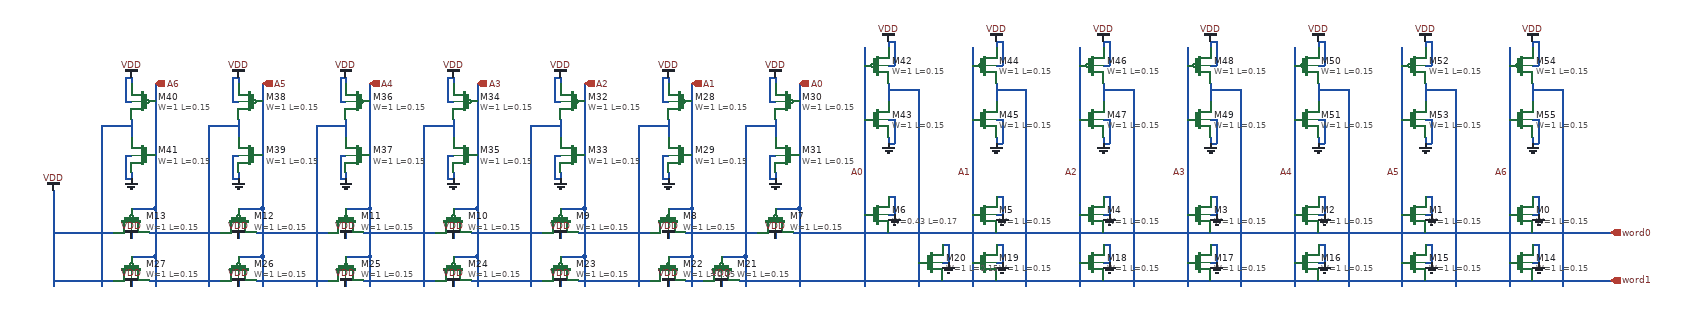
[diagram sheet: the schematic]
v {xschem version=3.4.6 file_version=1.2}
G {}
K {}
V {}
S {}
E {}
N 1450 -60 1450 0 { lab=#net1}
N 1360 -60 1360 0 { lab=A0}
N 1630 -60 1630 0 { lab=#net2}
N 1540 -60 1540 0 { lab=A1}
N 1810 -60 1810 0 { lab=#net3}
N 1720 -60 1720 0 { lab=A2}
N 1990 -60 1990 0 { lab=#net4}
N 1900 -60 1900 0 { lab=A3}
N 2170 -60 2170 0 { lab=#net5}
N 2080 -60 2080 0 { lab=A4}
N 2350 -60 2350 0 { lab=#net6}
N 2260 -60 2260 0 { lab=A5}
N 2530 -60 2530 0 { lab=#net7}
N 2440 -60 2440 0 { lab=A6}
N 1070 -60 1070 0 {lab=A1}
N 980 -30 980 0 {lab=#net8}
N 2530 0 2530 80 {lab=#net7}
N 2520 70 2610 70 {lab=word0}
N 2480 40 2490 40 {lab=GND}
N 2490 10 2490 40 {lab=GND}
N 2480 10 2490 10 {lab=GND}
N 2440 0 2440 40 {lab=A6}
N 2440 40 2440 80 {lab=A6}
N 2430 70 2480 70 {lab=word0}
N 2480 70 2520 70 {lab=word0}
N 2350 0 2350 80 {lab=#net6}
N 2340 70 2430 70 {lab=word0}
N 2300 40 2310 40 {lab=GND}
N 2310 10 2310 40 {lab=GND}
N 2300 10 2310 10 {lab=GND}
N 2260 0 2260 40 {lab=A5}
N 2260 40 2260 80 {lab=A5}
N 2250 70 2300 70 {lab=word0}
N 2300 70 2340 70 {lab=word0}
N 2170 0 2170 80 {lab=#net5}
N 2160 70 2250 70 {lab=word0}
N 2120 40 2130 40 {lab=GND}
N 2130 10 2130 40 {lab=GND}
N 2120 10 2130 10 {lab=GND}
N 2080 0 2080 40 {lab=A4}
N 2080 40 2080 80 {lab=A4}
N 2070 70 2120 70 {lab=word0}
N 2120 70 2160 70 {lab=word0}
N 1990 0 1990 80 {lab=#net4}
N 1980 70 2070 70 {lab=word0}
N 1940 40 1950 40 {lab=GND}
N 1950 10 1950 40 {lab=GND}
N 1940 10 1950 10 {lab=GND}
N 1900 0 1900 40 {lab=A3}
N 1900 40 1900 80 {lab=A3}
N 1890 70 1940 70 {lab=word0}
N 1940 70 1980 70 {lab=word0}
N 1810 0 1810 80 {lab=#net3}
N 1800 70 1890 70 {lab=word0}
N 1760 40 1770 40 {lab=GND}
N 1770 10 1770 40 {lab=GND}
N 1760 10 1770 10 {lab=GND}
N 1720 0 1720 40 {lab=A2}
N 1720 40 1720 80 {lab=A2}
N 1710 70 1760 70 {lab=word0}
N 1760 70 1800 70 {lab=word0}
N 1630 0 1630 80 {lab=#net2}
N 1620 70 1710 70 {lab=word0}
N 1580 40 1590 40 {lab=GND}
N 1590 10 1590 40 {lab=GND}
N 1580 10 1590 10 {lab=GND}
N 1540 0 1540 40 {lab=A1}
N 1540 40 1540 80 {lab=A1}
N 1530 70 1580 70 {lab=word0}
N 1580 70 1620 70 {lab=word0}
N 1450 0 1450 80 {lab=#net1}
N 1440 70 1530 70 {lab=word0}
N 1400 40 1410 40 {lab=GND}
N 1410 10 1410 40 {lab=GND}
N 1400 10 1410 10 {lab=GND}
N 1360 0 1360 40 {lab=A0}
N 1360 40 1360 80 {lab=A0}
N 1350 70 1400 70 {lab=word0}
N 1400 70 1440 70 {lab=word0}
N 1260 70 1350 70 { lab=word0}
N 1210 30 1250 30 {lab=A0}
N 1210 70 1210 80 {lab=VDD}
N 1240 70 1260 70 {lab=word0}
N 1170 70 1180 70 {lab=#net9}
N 1250 0 1250 30 {lab=A0}
N 1250 30 1250 80 {lab=A0}
N 1160 0 1160 80 {lab=#net10}
N 1080 70 1170 70 {lab=#net9}
N 1030 30 1070 30 {lab=A1}
N 1030 70 1030 80 {lab=VDD}
N 1060 70 1080 70 {lab=#net9}
N 990 70 1000 70 {lab=#net11}
N 1070 0 1070 30 {lab=A1}
N 1070 30 1070 80 {lab=A1}
N 980 0 980 80 {lab=#net8}
N 900 70 990 70 {lab=#net11}
N 850 30 890 30 {lab=A2}
N 850 70 850 80 {lab=VDD}
N 880 70 900 70 {lab=#net11}
N 810 70 820 70 {lab=#net12}
N 890 0 890 30 {lab=A2}
N 890 30 890 80 {lab=A2}
N 800 0 800 80 {lab=#net13}
N 720 70 810 70 {lab=#net12}
N 670 30 710 30 {lab=A3}
N 670 70 670 80 {lab=VDD}
N 700 70 720 70 {lab=#net12}
N 630 70 640 70 {lab=#net14}
N 710 0 710 30 {lab=A3}
N 710 30 710 80 {lab=A3}
N 620 0 620 80 {lab=#net15}
N 540 70 630 70 {lab=#net14}
N 490 30 530 30 {lab=A4}
N 490 70 490 80 {lab=VDD}
N 520 70 540 70 {lab=#net14}
N 450 70 460 70 {lab=#net16}
N 530 0 530 30 {lab=A4}
N 530 30 530 80 {lab=A4}
N 440 0 440 80 {lab=#net17}
N 360 70 450 70 {lab=#net16}
N 310 30 350 30 {lab=A5}
N 310 70 310 80 {lab=VDD}
N 340 70 360 70 {lab=#net16}
N 270 70 280 70 {lab=#net18}
N 350 0 350 30 {lab=A5}
N 350 30 350 80 {lab=A5}
N 260 0 260 80 {lab=#net19}
N 180 70 270 70 {lab=#net18}
N 130 30 170 30 {lab=A6}
N 130 70 130 80 {lab=VDD}
N 160 70 180 70 {lab=#net18}
N 90 70 100 70 {lab=VDD}
N 170 0 170 30 {lab=A6}
N 170 30 170 80 {lab=A6}
N 80 0 80 80 {lab=#net20}
N 0 70 90 70 {lab=VDD}
N 0 0 0 80 { lab=VDD}
N 2530 80 2530 160 {lab=#net7}
N 2520 150 2610 150 {lab=word1}
N 2480 120 2490 120 {lab=GND}
N 2490 90 2490 120 {lab=GND}
N 2480 90 2490 90 {lab=GND}
N 2440 80 2440 120 {lab=A6}
N 2440 120 2440 160 {lab=A6}
N 2430 150 2480 150 {lab=word1}
N 2480 150 2520 150 {lab=word1}
N 2350 80 2350 160 {lab=#net6}
N 2340 150 2430 150 {lab=word1}
N 2300 120 2310 120 {lab=GND}
N 2310 90 2310 120 {lab=GND}
N 2300 90 2310 90 {lab=GND}
N 2260 80 2260 120 {lab=A5}
N 2260 120 2260 160 {lab=A5}
N 2250 150 2300 150 {lab=word1}
N 2300 150 2340 150 {lab=word1}
N 2170 80 2170 160 {lab=#net5}
N 2160 150 2250 150 {lab=word1}
N 2120 120 2130 120 {lab=GND}
N 2130 90 2130 120 {lab=GND}
N 2120 90 2130 90 {lab=GND}
N 2080 80 2080 120 {lab=A4}
N 2080 120 2080 160 {lab=A4}
N 2070 150 2120 150 {lab=word1}
N 2120 150 2160 150 {lab=word1}
N 1990 80 1990 160 {lab=#net4}
N 1980 150 2070 150 {lab=word1}
N 1940 120 1950 120 {lab=GND}
N 1950 90 1950 120 {lab=GND}
N 1940 90 1950 90 {lab=GND}
N 1900 80 1900 120 {lab=A3}
N 1900 120 1900 160 {lab=A3}
N 1890 150 1940 150 {lab=word1}
N 1940 150 1980 150 {lab=word1}
N 1810 80 1810 160 {lab=#net3}
N 1800 150 1890 150 {lab=word1}
N 1760 120 1770 120 {lab=GND}
N 1770 90 1770 120 {lab=GND}
N 1760 90 1770 90 {lab=GND}
N 1720 80 1720 120 {lab=A2}
N 1720 120 1720 160 {lab=A2}
N 1710 150 1760 150 {lab=word1}
N 1760 150 1800 150 {lab=word1}
N 1630 80 1630 160 {lab=#net2}
N 1620 150 1710 150 {lab=word1}
N 1580 120 1590 120 {lab=GND}
N 1590 90 1590 120 {lab=GND}
N 1580 90 1590 90 {lab=GND}
N 1540 80 1540 120 {lab=A1}
N 1540 120 1540 160 {lab=A1}
N 1530 150 1580 150 {lab=word1}
N 1580 150 1620 150 {lab=word1}
N 1490 120 1500 120 {lab=GND}
N 1500 90 1500 120 {lab=GND}
N 1490 90 1500 90 {lab=GND}
N 1450 80 1450 120 {lab=#net1}
N 1450 120 1450 160 {lab=#net1}
N 1440 150 1490 150 {lab=word1}
N 1490 150 1530 150 {lab=word1}
N 1360 80 1360 160 {lab=A0}
N 1350 150 1440 150 {lab=word1}
N 1260 150 1350 150 { lab=word1}
N 1250 80 1250 160 {lab=A0}
N 1170 150 1260 150 {lab=word1}
N 1120 110 1160 110 {lab=#net10}
N 1120 150 1120 160 {lab=VDD}
N 1150 150 1170 150 {lab=word1}
N 1080 150 1090 150 {lab=#net21}
N 1160 80 1160 110 {lab=#net10}
N 1160 110 1160 160 {lab=#net10}
N 1030 110 1070 110 {lab=A1}
N 1030 150 1030 160 {lab=VDD}
N 1060 150 1080 150 {lab=#net21}
N 990 150 1000 150 {lab=#net22}
N 1070 80 1070 110 {lab=A1}
N 1070 110 1070 160 {lab=A1}
N 980 80 980 160 {lab=#net8}
N 900 150 990 150 {lab=#net22}
N 850 110 890 110 {lab=A2}
N 850 150 850 160 {lab=VDD}
N 880 150 900 150 {lab=#net22}
N 810 150 820 150 {lab=#net23}
N 890 80 890 110 {lab=A2}
N 890 110 890 160 {lab=A2}
N 800 80 800 160 {lab=#net13}
N 720 150 810 150 {lab=#net23}
N 670 110 710 110 {lab=A3}
N 670 150 670 160 {lab=VDD}
N 700 150 720 150 {lab=#net23}
N 630 150 640 150 {lab=#net24}
N 710 80 710 110 {lab=A3}
N 710 110 710 160 {lab=A3}
N 620 80 620 160 {lab=#net15}
N 540 150 630 150 {lab=#net24}
N 490 110 530 110 {lab=A4}
N 490 150 490 160 {lab=VDD}
N 520 150 540 150 {lab=#net24}
N 450 150 460 150 {lab=#net25}
N 530 80 530 110 {lab=A4}
N 530 110 530 160 {lab=A4}
N 440 80 440 160 {lab=#net17}
N 360 150 450 150 {lab=#net25}
N 310 110 350 110 {lab=A5}
N 310 150 310 160 {lab=VDD}
N 340 150 360 150 {lab=#net25}
N 270 150 280 150 {lab=#net26}
N 350 80 350 110 {lab=A5}
N 350 110 350 160 {lab=A5}
N 260 80 260 160 {lab=#net19}
N 180 150 270 150 {lab=#net26}
N 130 110 170 110 {lab=A6}
N 130 150 130 160 {lab=VDD}
N 160 150 180 150 {lab=#net26}
N 90 150 100 150 {lab=VDD}
N 170 80 170 110 {lab=A6}
N 170 110 170 160 {lab=A6}
N 80 80 80 160 {lab=#net20}
N 0 150 90 150 {lab=VDD}
N 0 80 0 160 { lab=VDD}
N 1070 -180 1070 -60 {lab=A1}
N 1020 -150 1030 -150 {lab=VDD}
N 1020 -190 1020 -150 {lab=VDD}
N 1020 -190 1030 -190 {lab=VDD}
N 1030 -190 1030 -180 {lab=VDD}
N 1030 -120 1030 -90 {lab=#net8}
N 1020 -60 1030 -60 {lab=GND}
N 1020 -60 1020 -20 {lab=GND}
N 1020 -20 1030 -20 {lab=GND}
N 1030 -30 1030 -20 {lab=GND}
N 980 -110 1030 -110 {lab=#net8}
N 980 -110 980 -30 {lab=#net8}
N 1250 -60 1250 0 {lab=A0}
N 1160 -30 1160 0 {lab=#net10}
N 1250 -180 1250 -60 {lab=A0}
N 1200 -150 1210 -150 {lab=VDD}
N 1200 -190 1200 -150 {lab=VDD}
N 1200 -190 1210 -190 {lab=VDD}
N 1210 -190 1210 -180 {lab=VDD}
N 1210 -120 1210 -90 {lab=#net10}
N 1200 -60 1210 -60 {lab=GND}
N 1200 -60 1200 -20 {lab=GND}
N 1200 -20 1210 -20 {lab=GND}
N 1210 -30 1210 -20 {lab=GND}
N 1160 -110 1210 -110 {lab=#net10}
N 1160 -110 1160 -30 {lab=#net10}
N 890 -60 890 0 {lab=A2}
N 800 -30 800 0 {lab=#net13}
N 890 -180 890 -60 {lab=A2}
N 840 -150 850 -150 {lab=VDD}
N 840 -190 840 -150 {lab=VDD}
N 840 -190 850 -190 {lab=VDD}
N 850 -190 850 -180 {lab=VDD}
N 850 -120 850 -90 {lab=#net13}
N 840 -60 850 -60 {lab=GND}
N 840 -60 840 -20 {lab=GND}
N 840 -20 850 -20 {lab=GND}
N 850 -30 850 -20 {lab=GND}
N 800 -110 850 -110 {lab=#net13}
N 800 -110 800 -30 {lab=#net13}
N 710 -60 710 0 {lab=A3}
N 620 -30 620 0 {lab=#net15}
N 710 -180 710 -60 {lab=A3}
N 660 -150 670 -150 {lab=VDD}
N 660 -190 660 -150 {lab=VDD}
N 660 -190 670 -190 {lab=VDD}
N 670 -190 670 -180 {lab=VDD}
N 670 -120 670 -90 {lab=#net15}
N 660 -60 670 -60 {lab=GND}
N 660 -60 660 -20 {lab=GND}
N 660 -20 670 -20 {lab=GND}
N 670 -30 670 -20 {lab=GND}
N 620 -110 670 -110 {lab=#net15}
N 620 -110 620 -30 {lab=#net15}
N 530 -60 530 0 {lab=A4}
N 440 -30 440 0 {lab=#net17}
N 530 -180 530 -60 {lab=A4}
N 480 -150 490 -150 {lab=VDD}
N 480 -190 480 -150 {lab=VDD}
N 480 -190 490 -190 {lab=VDD}
N 490 -190 490 -180 {lab=VDD}
N 490 -120 490 -90 {lab=#net17}
N 480 -60 490 -60 {lab=GND}
N 480 -60 480 -20 {lab=GND}
N 480 -20 490 -20 {lab=GND}
N 490 -30 490 -20 {lab=GND}
N 440 -110 490 -110 {lab=#net17}
N 440 -110 440 -30 {lab=#net17}
N 350 -60 350 0 {lab=A5}
N 260 -30 260 0 {lab=#net19}
N 350 -180 350 -60 {lab=A5}
N 300 -150 310 -150 {lab=VDD}
N 300 -190 300 -150 {lab=VDD}
N 300 -190 310 -190 {lab=VDD}
N 310 -190 310 -180 {lab=VDD}
N 310 -120 310 -90 {lab=#net19}
N 300 -60 310 -60 {lab=GND}
N 300 -60 300 -20 {lab=GND}
N 300 -20 310 -20 {lab=GND}
N 310 -30 310 -20 {lab=GND}
N 260 -110 310 -110 {lab=#net19}
N 260 -110 260 -30 {lab=#net19}
N 170 -60 170 0 {lab=A6}
N 80 -30 80 0 {lab=#net20}
N 170 -180 170 -60 {lab=A6}
N 120 -150 130 -150 {lab=VDD}
N 120 -190 120 -150 {lab=VDD}
N 120 -190 130 -190 {lab=VDD}
N 130 -190 130 -180 {lab=VDD}
N 130 -120 130 -90 {lab=#net20}
N 120 -60 130 -60 {lab=GND}
N 120 -60 120 -20 {lab=GND}
N 120 -20 130 -20 {lab=GND}
N 130 -30 130 -20 {lab=GND}
N 80 -110 130 -110 {lab=#net20}
N 80 -110 80 -30 {lab=#net20}
N 1360 -120 1360 -60 {lab=A0}
N 1450 -90 1450 -60 {lab=#net1}
N 1360 -240 1360 -120 {lab=A0}
N 1400 -210 1410 -210 {lab=VDD}
N 1410 -250 1410 -210 {lab=VDD}
N 1400 -250 1410 -250 {lab=VDD}
N 1400 -250 1400 -240 {lab=VDD}
N 1400 -180 1400 -150 {lab=#net1}
N 1400 -120 1410 -120 {lab=GND}
N 1410 -120 1410 -80 {lab=GND}
N 1400 -80 1410 -80 {lab=GND}
N 1400 -90 1400 -80 {lab=GND}
N 1400 -170 1450 -170 {lab=#net1}
N 1450 -170 1450 -90 {lab=#net1}
N 1540 -120 1540 -60 {lab=A1}
N 1630 -90 1630 -60 {lab=#net2}
N 1540 -240 1540 -120 {lab=A1}
N 1580 -210 1590 -210 {lab=VDD}
N 1590 -250 1590 -210 {lab=VDD}
N 1580 -250 1590 -250 {lab=VDD}
N 1580 -250 1580 -240 {lab=VDD}
N 1580 -180 1580 -150 {lab=#net2}
N 1580 -120 1590 -120 {lab=GND}
N 1590 -120 1590 -80 {lab=GND}
N 1580 -80 1590 -80 {lab=GND}
N 1580 -90 1580 -80 {lab=GND}
N 1580 -170 1630 -170 {lab=#net2}
N 1630 -170 1630 -90 {lab=#net2}
N 1720 -120 1720 -60 {lab=A2}
N 1810 -90 1810 -60 {lab=#net3}
N 1720 -240 1720 -120 {lab=A2}
N 1760 -210 1770 -210 {lab=VDD}
N 1770 -250 1770 -210 {lab=VDD}
N 1760 -250 1770 -250 {lab=VDD}
N 1760 -250 1760 -240 {lab=VDD}
N 1760 -180 1760 -150 {lab=#net3}
N 1760 -120 1770 -120 {lab=GND}
N 1770 -120 1770 -80 {lab=GND}
N 1760 -80 1770 -80 {lab=GND}
N 1760 -90 1760 -80 {lab=GND}
N 1760 -170 1810 -170 {lab=#net3}
N 1810 -170 1810 -90 {lab=#net3}
N 1900 -120 1900 -60 {lab=A3}
N 1990 -90 1990 -60 {lab=#net4}
N 1900 -240 1900 -120 {lab=A3}
N 1940 -210 1950 -210 {lab=VDD}
N 1950 -250 1950 -210 {lab=VDD}
N 1940 -250 1950 -250 {lab=VDD}
N 1940 -250 1940 -240 {lab=VDD}
N 1940 -180 1940 -150 {lab=#net4}
N 1940 -120 1950 -120 {lab=GND}
N 1950 -120 1950 -80 {lab=GND}
N 1940 -80 1950 -80 {lab=GND}
N 1940 -90 1940 -80 {lab=GND}
N 1940 -170 1990 -170 {lab=#net4}
N 1990 -170 1990 -90 {lab=#net4}
N 2080 -120 2080 -60 {lab=A4}
N 2170 -90 2170 -60 {lab=#net5}
N 2080 -240 2080 -120 {lab=A4}
N 2120 -210 2130 -210 {lab=VDD}
N 2130 -250 2130 -210 {lab=VDD}
N 2120 -250 2130 -250 {lab=VDD}
N 2120 -250 2120 -240 {lab=VDD}
N 2120 -180 2120 -150 {lab=#net5}
N 2120 -120 2130 -120 {lab=GND}
N 2130 -120 2130 -80 {lab=GND}
N 2120 -80 2130 -80 {lab=GND}
N 2120 -90 2120 -80 {lab=GND}
N 2120 -170 2170 -170 {lab=#net5}
N 2170 -170 2170 -90 {lab=#net5}
N 2260 -120 2260 -60 {lab=A5}
N 2350 -90 2350 -60 {lab=#net6}
N 2260 -240 2260 -120 {lab=A5}
N 2300 -210 2310 -210 {lab=VDD}
N 2310 -250 2310 -210 {lab=VDD}
N 2300 -250 2310 -250 {lab=VDD}
N 2300 -250 2300 -240 {lab=VDD}
N 2300 -180 2300 -150 {lab=#net6}
N 2300 -120 2310 -120 {lab=GND}
N 2310 -120 2310 -80 {lab=GND}
N 2300 -80 2310 -80 {lab=GND}
N 2300 -90 2300 -80 {lab=GND}
N 2300 -170 2350 -170 {lab=#net6}
N 2350 -170 2350 -90 {lab=#net6}
N 2440 -120 2440 -60 {lab=A6}
N 2530 -90 2530 -60 {lab=#net7}
N 2440 -240 2440 -120 {lab=A6}
N 2480 -210 2490 -210 {lab=VDD}
N 2490 -250 2490 -210 {lab=VDD}
N 2480 -250 2490 -250 {lab=VDD}
N 2480 -250 2480 -240 {lab=VDD}
N 2480 -180 2480 -150 {lab=#net7}
N 2480 -120 2490 -120 {lab=GND}
N 2490 -120 2490 -80 {lab=GND}
N 2480 -80 2490 -80 {lab=GND}
N 2480 -90 2480 -80 {lab=GND}
N 2480 -170 2530 -170 {lab=#net7}
N 2530 -170 2530 -90 {lab=#net7}
C {devices/vdd.sym} 0 0 0 0 {lab=VDD}
C {devices/lab_wire.sym} 1360 -30 0 0 {name=p1 lab=A0}
C {devices/lab_wire.sym} 1540 -30 0 0 {name=p3 lab=A1}
C {devices/lab_wire.sym} 1720 -30 0 0 {name=p5 lab=A2}
C {devices/lab_wire.sym} 1900 -30 0 0 {name=p7 lab=A3}
C {devices/lab_wire.sym} 2080 -30 0 0 {name=p9 lab=A4}
C {devices/lab_wire.sym} 2260 -30 0 0 {name=p11 lab=A5}
C {devices/lab_wire.sym} 2440 -30 0 0 {name=p13 lab=A6}
C {devices/ipin.sym} 1250 -180 3 1 {name=p14 lab=A0}
C {devices/ipin.sym} 1070 -180 3 1 {name=p16 lab=A1}
C {devices/ipin.sym} 890 -180 3 1 {name=p18 lab=A2}
C {devices/ipin.sym} 710 -180 3 1 {name=p20 lab=A3}
C {devices/ipin.sym} 530 -180 3 1 {name=p22 lab=A4}
C {devices/ipin.sym} 350 -180 3 1 {name=p24 lab=A5}
C {devices/ipin.sym} 170 -180 3 1 {name=p26 lab=A6}
C {devices/opin.sym} 2610 70 0 0 {name=p28 lab=word0}
C {sky130_fd_pr/nfet_01v8.sym} 2460 40 2 1 {name=M0
L=0.15
W=1
nf=1 
mult=1
ad="'int((nf+1)/2) * W/nf * 0.29'" 
pd="'2*int((nf+1)/2) * (W/nf + 0.29)'"
as="'int((nf+2)/2) * W/nf * 0.29'" 
ps="'2*int((nf+2)/2) * (W/nf + 0.29)'"
nrd="'0.29 / W'" nrs="'0.29 / W'"
sa=0 sb=0 sd=0
model=nfet_01v8
spiceprefix=X
}
C {devices/gnd.sym} 2490 40 3 0 {name=l0 lab=GND}
C {sky130_fd_pr/nfet_01v8.sym} 2280 40 2 1 {name=M1
L=0.15
W=1
nf=1 
mult=1
ad="'int((nf+1)/2) * W/nf * 0.29'" 
pd="'2*int((nf+1)/2) * (W/nf + 0.29)'"
as="'int((nf+2)/2) * W/nf * 0.29'" 
ps="'2*int((nf+2)/2) * (W/nf + 0.29)'"
nrd="'0.29 / W'" nrs="'0.29 / W'"
sa=0 sb=0 sd=0
model=nfet_01v8
spiceprefix=X
}
C {devices/gnd.sym} 2310 40 3 0 {name=l1 lab=GND}
C {sky130_fd_pr/nfet_01v8.sym} 2100 40 2 1 {name=M2
L=0.15
W=1
nf=1 
mult=1
ad="'int((nf+1)/2) * W/nf * 0.29'" 
pd="'2*int((nf+1)/2) * (W/nf + 0.29)'"
as="'int((nf+2)/2) * W/nf * 0.29'" 
ps="'2*int((nf+2)/2) * (W/nf + 0.29)'"
nrd="'0.29 / W'" nrs="'0.29 / W'"
sa=0 sb=0 sd=0
model=nfet_01v8
spiceprefix=X
}
C {devices/gnd.sym} 2130 40 3 0 {name=l2 lab=GND}
C {sky130_fd_pr/nfet_01v8.sym} 1920 40 2 1 {name=M3
L=0.15
W=1
nf=1 
mult=1
ad="'int((nf+1)/2) * W/nf * 0.29'" 
pd="'2*int((nf+1)/2) * (W/nf + 0.29)'"
as="'int((nf+2)/2) * W/nf * 0.29'" 
ps="'2*int((nf+2)/2) * (W/nf + 0.29)'"
nrd="'0.29 / W'" nrs="'0.29 / W'"
sa=0 sb=0 sd=0
model=nfet_01v8
spiceprefix=X
}
C {devices/gnd.sym} 1950 40 3 0 {name=l3 lab=GND}
C {sky130_fd_pr/nfet_01v8.sym} 1740 40 2 1 {name=M4
L=0.15
W=1
nf=1 
mult=1
ad="'int((nf+1)/2) * W/nf * 0.29'" 
pd="'2*int((nf+1)/2) * (W/nf + 0.29)'"
as="'int((nf+2)/2) * W/nf * 0.29'" 
ps="'2*int((nf+2)/2) * (W/nf + 0.29)'"
nrd="'0.29 / W'" nrs="'0.29 / W'"
sa=0 sb=0 sd=0
model=nfet_01v8
spiceprefix=X
}
C {devices/gnd.sym} 1770 40 3 0 {name=l4 lab=GND}
C {sky130_fd_pr/nfet_01v8.sym} 1560 40 2 1 {name=M5
L=0.15
W=1
nf=1 
mult=1
ad="'int((nf+1)/2) * W/nf * 0.29'" 
pd="'2*int((nf+1)/2) * (W/nf + 0.29)'"
as="'int((nf+2)/2) * W/nf * 0.29'" 
ps="'2*int((nf+2)/2) * (W/nf + 0.29)'"
nrd="'0.29 / W'" nrs="'0.29 / W'"
sa=0 sb=0 sd=0
model=nfet_01v8
spiceprefix=X
}
C {devices/gnd.sym} 1590 40 3 0 {name=l5 lab=GND}
C {sky130_fd_pr/nfet_01v8.sym} 1380 40 2 1 {name=M6
L=0.17
W=0.43
nf=1 
mult=1
ad="'int((nf+1)/2) * W/nf * 0.29'" 
pd="'2*int((nf+1)/2) * (W/nf + 0.29)'"
as="'int((nf+2)/2) * W/nf * 0.29'" 
ps="'2*int((nf+2)/2) * (W/nf + 0.29)'"
nrd="'0.29 / W'" nrs="'0.29 / W'"
sa=0 sb=0 sd=0
model=nfet_01v8
spiceprefix=X
}
C {devices/gnd.sym} 1410 40 3 0 {name=l6 lab=GND}
C {sky130_fd_pr/pfet_01v8.sym} 1210 50 3 1 {name=M7
L=0.15
W=1
nf=1
mult=1
ad="'int((nf+1)/2) * W/nf * 0.29'" 
pd="'2*int((nf+1)/2) * (W/nf + 0.29)'"
as="'int((nf+2)/2) * W/nf * 0.29'" 
ps="'2*int((nf+2)/2) * (W/nf + 0.29)'"
nrd="'0.29 / W'" nrs="'0.29 / W'"
sa=0 sb=0 sd=0
model=pfet_01v8
spiceprefix=X
}
C {devices/vdd.sym} 1210 80 3 0 {name=l7 lab=VDD}
C {sky130_fd_pr/pfet_01v8.sym} 1030 50 3 1 {name=M8
L=0.15
W=1
nf=1
mult=1
ad="'int((nf+1)/2) * W/nf * 0.29'" 
pd="'2*int((nf+1)/2) * (W/nf + 0.29)'"
as="'int((nf+2)/2) * W/nf * 0.29'" 
ps="'2*int((nf+2)/2) * (W/nf + 0.29)'"
nrd="'0.29 / W'" nrs="'0.29 / W'"
sa=0 sb=0 sd=0
model=pfet_01v8
spiceprefix=X
}
C {devices/vdd.sym} 1030 80 3 0 {name=l8 lab=VDD}
C {sky130_fd_pr/pfet_01v8.sym} 850 50 3 1 {name=M9
L=0.15
W=1
nf=1
mult=1
ad="'int((nf+1)/2) * W/nf * 0.29'" 
pd="'2*int((nf+1)/2) * (W/nf + 0.29)'"
as="'int((nf+2)/2) * W/nf * 0.29'" 
ps="'2*int((nf+2)/2) * (W/nf + 0.29)'"
nrd="'0.29 / W'" nrs="'0.29 / W'"
sa=0 sb=0 sd=0
model=pfet_01v8
spiceprefix=X
}
C {devices/vdd.sym} 850 80 3 0 {name=l9 lab=VDD}
C {sky130_fd_pr/pfet_01v8.sym} 670 50 3 1 {name=M10
L=0.15
W=1
nf=1
mult=1
ad="'int((nf+1)/2) * W/nf * 0.29'" 
pd="'2*int((nf+1)/2) * (W/nf + 0.29)'"
as="'int((nf+2)/2) * W/nf * 0.29'" 
ps="'2*int((nf+2)/2) * (W/nf + 0.29)'"
nrd="'0.29 / W'" nrs="'0.29 / W'"
sa=0 sb=0 sd=0
model=pfet_01v8
spiceprefix=X
}
C {devices/vdd.sym} 670 80 3 0 {name=l10 lab=VDD}
C {sky130_fd_pr/pfet_01v8.sym} 490 50 3 1 {name=M11
L=0.15
W=1
nf=1
mult=1
ad="'int((nf+1)/2) * W/nf * 0.29'" 
pd="'2*int((nf+1)/2) * (W/nf + 0.29)'"
as="'int((nf+2)/2) * W/nf * 0.29'" 
ps="'2*int((nf+2)/2) * (W/nf + 0.29)'"
nrd="'0.29 / W'" nrs="'0.29 / W'"
sa=0 sb=0 sd=0
model=pfet_01v8
spiceprefix=X
}
C {devices/vdd.sym} 490 80 3 0 {name=l11 lab=VDD}
C {sky130_fd_pr/pfet_01v8.sym} 310 50 3 1 {name=M12
L=0.15
W=1
nf=1
mult=1
ad="'int((nf+1)/2) * W/nf * 0.29'" 
pd="'2*int((nf+1)/2) * (W/nf + 0.29)'"
as="'int((nf+2)/2) * W/nf * 0.29'" 
ps="'2*int((nf+2)/2) * (W/nf + 0.29)'"
nrd="'0.29 / W'" nrs="'0.29 / W'"
sa=0 sb=0 sd=0
model=pfet_01v8
spiceprefix=X
}
C {devices/vdd.sym} 310 80 3 0 {name=l12 lab=VDD}
C {sky130_fd_pr/pfet_01v8.sym} 130 50 3 1 {name=M13
L=0.15
W=1
nf=1
mult=1
ad="'int((nf+1)/2) * W/nf * 0.29'" 
pd="'2*int((nf+1)/2) * (W/nf + 0.29)'"
as="'int((nf+2)/2) * W/nf * 0.29'" 
ps="'2*int((nf+2)/2) * (W/nf + 0.29)'"
nrd="'0.29 / W'" nrs="'0.29 / W'"
sa=0 sb=0 sd=0
model=pfet_01v8
spiceprefix=X
}
C {devices/vdd.sym} 130 80 3 0 {name=l13 lab=VDD}
C {devices/opin.sym} 2610 150 0 0 {name=p29 lab=word1}
C {sky130_fd_pr/nfet_01v8.sym} 2460 120 2 1 {name=M14
L=0.15
W=1
nf=1 
mult=1
ad="'int((nf+1)/2) * W/nf * 0.29'" 
pd="'2*int((nf+1)/2) * (W/nf + 0.29)'"
as="'int((nf+2)/2) * W/nf * 0.29'" 
ps="'2*int((nf+2)/2) * (W/nf + 0.29)'"
nrd="'0.29 / W'" nrs="'0.29 / W'"
sa=0 sb=0 sd=0
model=nfet_01v8
spiceprefix=X
}
C {devices/gnd.sym} 2490 120 3 0 {name=l14 lab=GND}
C {sky130_fd_pr/nfet_01v8.sym} 2280 120 2 1 {name=M15
L=0.15
W=1
nf=1 
mult=1
ad="'int((nf+1)/2) * W/nf * 0.29'" 
pd="'2*int((nf+1)/2) * (W/nf + 0.29)'"
as="'int((nf+2)/2) * W/nf * 0.29'" 
ps="'2*int((nf+2)/2) * (W/nf + 0.29)'"
nrd="'0.29 / W'" nrs="'0.29 / W'"
sa=0 sb=0 sd=0
model=nfet_01v8
spiceprefix=X
}
C {devices/gnd.sym} 2310 120 3 0 {name=l15 lab=GND}
C {sky130_fd_pr/nfet_01v8.sym} 2100 120 2 1 {name=M16
L=0.15
W=1
nf=1 
mult=1
ad="'int((nf+1)/2) * W/nf * 0.29'" 
pd="'2*int((nf+1)/2) * (W/nf + 0.29)'"
as="'int((nf+2)/2) * W/nf * 0.29'" 
ps="'2*int((nf+2)/2) * (W/nf + 0.29)'"
nrd="'0.29 / W'" nrs="'0.29 / W'"
sa=0 sb=0 sd=0
model=nfet_01v8
spiceprefix=X
}
C {devices/gnd.sym} 2130 120 3 0 {name=l16 lab=GND}
C {sky130_fd_pr/nfet_01v8.sym} 1920 120 2 1 {name=M17
L=0.15
W=1
nf=1 
mult=1
ad="'int((nf+1)/2) * W/nf * 0.29'" 
pd="'2*int((nf+1)/2) * (W/nf + 0.29)'"
as="'int((nf+2)/2) * W/nf * 0.29'" 
ps="'2*int((nf+2)/2) * (W/nf + 0.29)'"
nrd="'0.29 / W'" nrs="'0.29 / W'"
sa=0 sb=0 sd=0
model=nfet_01v8
spiceprefix=X
}
C {devices/gnd.sym} 1950 120 3 0 {name=l17 lab=GND}
C {sky130_fd_pr/nfet_01v8.sym} 1740 120 2 1 {name=M18
L=0.15
W=1
nf=1 
mult=1
ad="'int((nf+1)/2) * W/nf * 0.29'" 
pd="'2*int((nf+1)/2) * (W/nf + 0.29)'"
as="'int((nf+2)/2) * W/nf * 0.29'" 
ps="'2*int((nf+2)/2) * (W/nf + 0.29)'"
nrd="'0.29 / W'" nrs="'0.29 / W'"
sa=0 sb=0 sd=0
model=nfet_01v8
spiceprefix=X
}
C {devices/gnd.sym} 1770 120 3 0 {name=l18 lab=GND}
C {sky130_fd_pr/nfet_01v8.sym} 1560 120 2 1 {name=M19
L=0.15
W=1
nf=1 
mult=1
ad="'int((nf+1)/2) * W/nf * 0.29'" 
pd="'2*int((nf+1)/2) * (W/nf + 0.29)'"
as="'int((nf+2)/2) * W/nf * 0.29'" 
ps="'2*int((nf+2)/2) * (W/nf + 0.29)'"
nrd="'0.29 / W'" nrs="'0.29 / W'"
sa=0 sb=0 sd=0
model=nfet_01v8
spiceprefix=X
}
C {devices/gnd.sym} 1590 120 3 0 {name=l19 lab=GND}
C {sky130_fd_pr/nfet_01v8.sym} 1470 120 2 1 {name=M20
L=0.15
W=1
nf=1 
mult=1
ad="'int((nf+1)/2) * W/nf * 0.29'" 
pd="'2*int((nf+1)/2) * (W/nf + 0.29)'"
as="'int((nf+2)/2) * W/nf * 0.29'" 
ps="'2*int((nf+2)/2) * (W/nf + 0.29)'"
nrd="'0.29 / W'" nrs="'0.29 / W'"
sa=0 sb=0 sd=0
model=nfet_01v8
spiceprefix=X
}
C {devices/gnd.sym} 1500 120 3 0 {name=l20 lab=GND}
C {sky130_fd_pr/pfet_01v8.sym} 1120 130 3 1 {name=M21
L=0.15
W=1
nf=1
mult=1
ad="'int((nf+1)/2) * W/nf * 0.29'" 
pd="'2*int((nf+1)/2) * (W/nf + 0.29)'"
as="'int((nf+2)/2) * W/nf * 0.29'" 
ps="'2*int((nf+2)/2) * (W/nf + 0.29)'"
nrd="'0.29 / W'" nrs="'0.29 / W'"
sa=0 sb=0 sd=0
model=pfet_01v8
spiceprefix=X
}
C {devices/vdd.sym} 1120 160 3 0 {name=l21 lab=VDD}
C {sky130_fd_pr/pfet_01v8.sym} 1030 130 3 1 {name=M22
L=0.15
W=1
nf=1
mult=1
ad="'int((nf+1)/2) * W/nf * 0.29'" 
pd="'2*int((nf+1)/2) * (W/nf + 0.29)'"
as="'int((nf+2)/2) * W/nf * 0.29'" 
ps="'2*int((nf+2)/2) * (W/nf + 0.29)'"
nrd="'0.29 / W'" nrs="'0.29 / W'"
sa=0 sb=0 sd=0
model=pfet_01v8
spiceprefix=X
}
C {devices/vdd.sym} 1030 160 3 0 {name=l22 lab=VDD}
C {sky130_fd_pr/pfet_01v8.sym} 850 130 3 1 {name=M23
L=0.15
W=1
nf=1
mult=1
ad="'int((nf+1)/2) * W/nf * 0.29'" 
pd="'2*int((nf+1)/2) * (W/nf + 0.29)'"
as="'int((nf+2)/2) * W/nf * 0.29'" 
ps="'2*int((nf+2)/2) * (W/nf + 0.29)'"
nrd="'0.29 / W'" nrs="'0.29 / W'"
sa=0 sb=0 sd=0
model=pfet_01v8
spiceprefix=X
}
C {devices/vdd.sym} 850 160 3 0 {name=l23 lab=VDD}
C {sky130_fd_pr/pfet_01v8.sym} 670 130 3 1 {name=M24
L=0.15
W=1
nf=1
mult=1
ad="'int((nf+1)/2) * W/nf * 0.29'" 
pd="'2*int((nf+1)/2) * (W/nf + 0.29)'"
as="'int((nf+2)/2) * W/nf * 0.29'" 
ps="'2*int((nf+2)/2) * (W/nf + 0.29)'"
nrd="'0.29 / W'" nrs="'0.29 / W'"
sa=0 sb=0 sd=0
model=pfet_01v8
spiceprefix=X
}
C {devices/vdd.sym} 670 160 3 0 {name=l24 lab=VDD}
C {sky130_fd_pr/pfet_01v8.sym} 490 130 3 1 {name=M25
L=0.15
W=1
nf=1
mult=1
ad="'int((nf+1)/2) * W/nf * 0.29'" 
pd="'2*int((nf+1)/2) * (W/nf + 0.29)'"
as="'int((nf+2)/2) * W/nf * 0.29'" 
ps="'2*int((nf+2)/2) * (W/nf + 0.29)'"
nrd="'0.29 / W'" nrs="'0.29 / W'"
sa=0 sb=0 sd=0
model=pfet_01v8
spiceprefix=X
}
C {devices/vdd.sym} 490 160 3 0 {name=l25 lab=VDD}
C {sky130_fd_pr/pfet_01v8.sym} 310 130 3 1 {name=M26
L=0.15
W=1
nf=1
mult=1
ad="'int((nf+1)/2) * W/nf * 0.29'" 
pd="'2*int((nf+1)/2) * (W/nf + 0.29)'"
as="'int((nf+2)/2) * W/nf * 0.29'" 
ps="'2*int((nf+2)/2) * (W/nf + 0.29)'"
nrd="'0.29 / W'" nrs="'0.29 / W'"
sa=0 sb=0 sd=0
model=pfet_01v8
spiceprefix=X
}
C {devices/vdd.sym} 310 160 3 0 {name=l26 lab=VDD}
C {sky130_fd_pr/pfet_01v8.sym} 130 130 3 1 {name=M27
L=0.15
W=1
nf=1
mult=1
ad="'int((nf+1)/2) * W/nf * 0.29'" 
pd="'2*int((nf+1)/2) * (W/nf + 0.29)'"
as="'int((nf+2)/2) * W/nf * 0.29'" 
ps="'2*int((nf+2)/2) * (W/nf + 0.29)'"
nrd="'0.29 / W'" nrs="'0.29 / W'"
sa=0 sb=0 sd=0
model=pfet_01v8
spiceprefix=X
}
C {devices/vdd.sym} 130 160 3 0 {name=l27 lab=VDD}
C {sky130_fd_pr/pfet_01v8.sym} 1050 -150 2 0 {name=M28
L=0.15
W=1
nf=1
mult=1
ad="'int((nf+1)/2) * W/nf * 0.29'" 
pd="'2*int((nf+1)/2) * (W/nf + 0.29)'"
as="'int((nf+2)/2) * W/nf * 0.29'" 
ps="'2*int((nf+2)/2) * (W/nf + 0.29)'"
nrd="'0.29 / W'" nrs="'0.29 / W'"
sa=0 sb=0 sd=0
model=pfet_01v8
spiceprefix=X
}
C {sky130_fd_pr/nfet_01v8.sym} 1050 -60 2 0 {name=M29
L=0.15
W=1
nf=1 
mult=1
ad="'int((nf+1)/2) * W/nf * 0.29'" 
pd="'2*int((nf+1)/2) * (W/nf + 0.29)'"
as="'int((nf+2)/2) * W/nf * 0.29'" 
ps="'2*int((nf+2)/2) * (W/nf + 0.29)'"
nrd="'0.29 / W'" nrs="'0.29 / W'"
sa=0 sb=0 sd=0
model=nfet_01v8
spiceprefix=X
}
C {devices/vdd.sym} 1030 -190 0 0 {lab=VDD}
C {devices/gnd.sym} 1030 -20 0 0 {name=l28 lab=GND}
C {sky130_fd_pr/pfet_01v8.sym} 1230 -150 2 0 {name=M30
L=0.15
W=1
nf=1
mult=1
ad="'int((nf+1)/2) * W/nf * 0.29'" 
pd="'2*int((nf+1)/2) * (W/nf + 0.29)'"
as="'int((nf+2)/2) * W/nf * 0.29'" 
ps="'2*int((nf+2)/2) * (W/nf + 0.29)'"
nrd="'0.29 / W'" nrs="'0.29 / W'"
sa=0 sb=0 sd=0
model=pfet_01v8
spiceprefix=X
}
C {sky130_fd_pr/nfet_01v8.sym} 1230 -60 2 0 {name=M31
L=0.15
W=1
nf=1 
mult=1
ad="'int((nf+1)/2) * W/nf * 0.29'" 
pd="'2*int((nf+1)/2) * (W/nf + 0.29)'"
as="'int((nf+2)/2) * W/nf * 0.29'" 
ps="'2*int((nf+2)/2) * (W/nf + 0.29)'"
nrd="'0.29 / W'" nrs="'0.29 / W'"
sa=0 sb=0 sd=0
model=nfet_01v8
spiceprefix=X
}
C {devices/vdd.sym} 1210 -190 0 0 {lab=VDD}
C {devices/gnd.sym} 1210 -20 0 0 {name=l29 lab=GND}
C {sky130_fd_pr/pfet_01v8.sym} 870 -150 2 0 {name=M32
L=0.15
W=1
nf=1
mult=1
ad="'int((nf+1)/2) * W/nf * 0.29'" 
pd="'2*int((nf+1)/2) * (W/nf + 0.29)'"
as="'int((nf+2)/2) * W/nf * 0.29'" 
ps="'2*int((nf+2)/2) * (W/nf + 0.29)'"
nrd="'0.29 / W'" nrs="'0.29 / W'"
sa=0 sb=0 sd=0
model=pfet_01v8
spiceprefix=X
}
C {sky130_fd_pr/nfet_01v8.sym} 870 -60 2 0 {name=M33
L=0.15
W=1
nf=1 
mult=1
ad="'int((nf+1)/2) * W/nf * 0.29'" 
pd="'2*int((nf+1)/2) * (W/nf + 0.29)'"
as="'int((nf+2)/2) * W/nf * 0.29'" 
ps="'2*int((nf+2)/2) * (W/nf + 0.29)'"
nrd="'0.29 / W'" nrs="'0.29 / W'"
sa=0 sb=0 sd=0
model=nfet_01v8
spiceprefix=X
}
C {devices/vdd.sym} 850 -190 0 0 {lab=VDD}
C {devices/gnd.sym} 850 -20 0 0 {name=l30 lab=GND}
C {sky130_fd_pr/pfet_01v8.sym} 690 -150 2 0 {name=M34
L=0.15
W=1
nf=1
mult=1
ad="'int((nf+1)/2) * W/nf * 0.29'" 
pd="'2*int((nf+1)/2) * (W/nf + 0.29)'"
as="'int((nf+2)/2) * W/nf * 0.29'" 
ps="'2*int((nf+2)/2) * (W/nf + 0.29)'"
nrd="'0.29 / W'" nrs="'0.29 / W'"
sa=0 sb=0 sd=0
model=pfet_01v8
spiceprefix=X
}
C {sky130_fd_pr/nfet_01v8.sym} 690 -60 2 0 {name=M35
L=0.15
W=1
nf=1 
mult=1
ad="'int((nf+1)/2) * W/nf * 0.29'" 
pd="'2*int((nf+1)/2) * (W/nf + 0.29)'"
as="'int((nf+2)/2) * W/nf * 0.29'" 
ps="'2*int((nf+2)/2) * (W/nf + 0.29)'"
nrd="'0.29 / W'" nrs="'0.29 / W'"
sa=0 sb=0 sd=0
model=nfet_01v8
spiceprefix=X
}
C {devices/vdd.sym} 670 -190 0 0 {lab=VDD}
C {devices/gnd.sym} 670 -20 0 0 {name=l31 lab=GND}
C {sky130_fd_pr/pfet_01v8.sym} 510 -150 2 0 {name=M36
L=0.15
W=1
nf=1
mult=1
ad="'int((nf+1)/2) * W/nf * 0.29'" 
pd="'2*int((nf+1)/2) * (W/nf + 0.29)'"
as="'int((nf+2)/2) * W/nf * 0.29'" 
ps="'2*int((nf+2)/2) * (W/nf + 0.29)'"
nrd="'0.29 / W'" nrs="'0.29 / W'"
sa=0 sb=0 sd=0
model=pfet_01v8
spiceprefix=X
}
C {sky130_fd_pr/nfet_01v8.sym} 510 -60 2 0 {name=M37
L=0.15
W=1
nf=1 
mult=1
ad="'int((nf+1)/2) * W/nf * 0.29'" 
pd="'2*int((nf+1)/2) * (W/nf + 0.29)'"
as="'int((nf+2)/2) * W/nf * 0.29'" 
ps="'2*int((nf+2)/2) * (W/nf + 0.29)'"
nrd="'0.29 / W'" nrs="'0.29 / W'"
sa=0 sb=0 sd=0
model=nfet_01v8
spiceprefix=X
}
C {devices/vdd.sym} 490 -190 0 0 {lab=VDD}
C {devices/gnd.sym} 490 -20 0 0 {name=l32 lab=GND}
C {sky130_fd_pr/pfet_01v8.sym} 330 -150 2 0 {name=M38
L=0.15
W=1
nf=1
mult=1
ad="'int((nf+1)/2) * W/nf * 0.29'" 
pd="'2*int((nf+1)/2) * (W/nf + 0.29)'"
as="'int((nf+2)/2) * W/nf * 0.29'" 
ps="'2*int((nf+2)/2) * (W/nf + 0.29)'"
nrd="'0.29 / W'" nrs="'0.29 / W'"
sa=0 sb=0 sd=0
model=pfet_01v8
spiceprefix=X
}
C {sky130_fd_pr/nfet_01v8.sym} 330 -60 2 0 {name=M39
L=0.15
W=1
nf=1 
mult=1
ad="'int((nf+1)/2) * W/nf * 0.29'" 
pd="'2*int((nf+1)/2) * (W/nf + 0.29)'"
as="'int((nf+2)/2) * W/nf * 0.29'" 
ps="'2*int((nf+2)/2) * (W/nf + 0.29)'"
nrd="'0.29 / W'" nrs="'0.29 / W'"
sa=0 sb=0 sd=0
model=nfet_01v8
spiceprefix=X
}
C {devices/vdd.sym} 310 -190 0 0 {lab=VDD}
C {devices/gnd.sym} 310 -20 0 0 {name=l33 lab=GND}
C {sky130_fd_pr/pfet_01v8.sym} 150 -150 2 0 {name=M40
L=0.15
W=1
nf=1
mult=1
ad="'int((nf+1)/2) * W/nf * 0.29'" 
pd="'2*int((nf+1)/2) * (W/nf + 0.29)'"
as="'int((nf+2)/2) * W/nf * 0.29'" 
ps="'2*int((nf+2)/2) * (W/nf + 0.29)'"
nrd="'0.29 / W'" nrs="'0.29 / W'"
sa=0 sb=0 sd=0
model=pfet_01v8
spiceprefix=X
}
C {sky130_fd_pr/nfet_01v8.sym} 150 -60 2 0 {name=M41
L=0.15
W=1
nf=1 
mult=1
ad="'int((nf+1)/2) * W/nf * 0.29'" 
pd="'2*int((nf+1)/2) * (W/nf + 0.29)'"
as="'int((nf+2)/2) * W/nf * 0.29'" 
ps="'2*int((nf+2)/2) * (W/nf + 0.29)'"
nrd="'0.29 / W'" nrs="'0.29 / W'"
sa=0 sb=0 sd=0
model=nfet_01v8
spiceprefix=X
}
C {devices/vdd.sym} 130 -190 0 0 {lab=VDD}
C {devices/gnd.sym} 130 -20 0 0 {name=l34 lab=GND}
C {sky130_fd_pr/pfet_01v8.sym} 1380 -210 2 1 {name=M42
L=0.15
W=1
nf=1
mult=1
ad="'int((nf+1)/2) * W/nf * 0.29'" 
pd="'2*int((nf+1)/2) * (W/nf + 0.29)'"
as="'int((nf+2)/2) * W/nf * 0.29'" 
ps="'2*int((nf+2)/2) * (W/nf + 0.29)'"
nrd="'0.29 / W'" nrs="'0.29 / W'"
sa=0 sb=0 sd=0
model=pfet_01v8
spiceprefix=X
}
C {sky130_fd_pr/nfet_01v8.sym} 1380 -120 2 1 {name=M43
L=0.15
W=1
nf=1 
mult=1
ad="'int((nf+1)/2) * W/nf * 0.29'" 
pd="'2*int((nf+1)/2) * (W/nf + 0.29)'"
as="'int((nf+2)/2) * W/nf * 0.29'" 
ps="'2*int((nf+2)/2) * (W/nf + 0.29)'"
nrd="'0.29 / W'" nrs="'0.29 / W'"
sa=0 sb=0 sd=0
model=nfet_01v8
spiceprefix=X
}
C {devices/vdd.sym} 1400 -250 0 1 {lab=VDD}
C {devices/gnd.sym} 1400 -80 0 1 {name=l35 lab=GND}
C {sky130_fd_pr/pfet_01v8.sym} 1560 -210 2 1 {name=M44
L=0.15
W=1
nf=1
mult=1
ad="'int((nf+1)/2) * W/nf * 0.29'" 
pd="'2*int((nf+1)/2) * (W/nf + 0.29)'"
as="'int((nf+2)/2) * W/nf * 0.29'" 
ps="'2*int((nf+2)/2) * (W/nf + 0.29)'"
nrd="'0.29 / W'" nrs="'0.29 / W'"
sa=0 sb=0 sd=0
model=pfet_01v8
spiceprefix=X
}
C {sky130_fd_pr/nfet_01v8.sym} 1560 -120 2 1 {name=M45
L=0.15
W=1
nf=1 
mult=1
ad="'int((nf+1)/2) * W/nf * 0.29'" 
pd="'2*int((nf+1)/2) * (W/nf + 0.29)'"
as="'int((nf+2)/2) * W/nf * 0.29'" 
ps="'2*int((nf+2)/2) * (W/nf + 0.29)'"
nrd="'0.29 / W'" nrs="'0.29 / W'"
sa=0 sb=0 sd=0
model=nfet_01v8
spiceprefix=X
}
C {devices/vdd.sym} 1580 -250 0 1 {lab=VDD}
C {devices/gnd.sym} 1580 -80 0 1 {name=l36 lab=GND}
C {sky130_fd_pr/pfet_01v8.sym} 1740 -210 2 1 {name=M46
L=0.15
W=1
nf=1
mult=1
ad="'int((nf+1)/2) * W/nf * 0.29'" 
pd="'2*int((nf+1)/2) * (W/nf + 0.29)'"
as="'int((nf+2)/2) * W/nf * 0.29'" 
ps="'2*int((nf+2)/2) * (W/nf + 0.29)'"
nrd="'0.29 / W'" nrs="'0.29 / W'"
sa=0 sb=0 sd=0
model=pfet_01v8
spiceprefix=X
}
C {sky130_fd_pr/nfet_01v8.sym} 1740 -120 2 1 {name=M47
L=0.15
W=1
nf=1 
mult=1
ad="'int((nf+1)/2) * W/nf * 0.29'" 
pd="'2*int((nf+1)/2) * (W/nf + 0.29)'"
as="'int((nf+2)/2) * W/nf * 0.29'" 
ps="'2*int((nf+2)/2) * (W/nf + 0.29)'"
nrd="'0.29 / W'" nrs="'0.29 / W'"
sa=0 sb=0 sd=0
model=nfet_01v8
spiceprefix=X
}
C {devices/vdd.sym} 1760 -250 0 1 {lab=VDD}
C {devices/gnd.sym} 1760 -80 0 1 {name=l37 lab=GND}
C {sky130_fd_pr/pfet_01v8.sym} 1920 -210 2 1 {name=M48
L=0.15
W=1
nf=1
mult=1
ad="'int((nf+1)/2) * W/nf * 0.29'" 
pd="'2*int((nf+1)/2) * (W/nf + 0.29)'"
as="'int((nf+2)/2) * W/nf * 0.29'" 
ps="'2*int((nf+2)/2) * (W/nf + 0.29)'"
nrd="'0.29 / W'" nrs="'0.29 / W'"
sa=0 sb=0 sd=0
model=pfet_01v8
spiceprefix=X
}
C {sky130_fd_pr/nfet_01v8.sym} 1920 -120 2 1 {name=M49
L=0.15
W=1
nf=1 
mult=1
ad="'int((nf+1)/2) * W/nf * 0.29'" 
pd="'2*int((nf+1)/2) * (W/nf + 0.29)'"
as="'int((nf+2)/2) * W/nf * 0.29'" 
ps="'2*int((nf+2)/2) * (W/nf + 0.29)'"
nrd="'0.29 / W'" nrs="'0.29 / W'"
sa=0 sb=0 sd=0
model=nfet_01v8
spiceprefix=X
}
C {devices/vdd.sym} 1940 -250 0 1 {lab=VDD}
C {devices/gnd.sym} 1940 -80 0 1 {name=l38 lab=GND}
C {sky130_fd_pr/pfet_01v8.sym} 2100 -210 2 1 {name=M50
L=0.15
W=1
nf=1
mult=1
ad="'int((nf+1)/2) * W/nf * 0.29'" 
pd="'2*int((nf+1)/2) * (W/nf + 0.29)'"
as="'int((nf+2)/2) * W/nf * 0.29'" 
ps="'2*int((nf+2)/2) * (W/nf + 0.29)'"
nrd="'0.29 / W'" nrs="'0.29 / W'"
sa=0 sb=0 sd=0
model=pfet_01v8
spiceprefix=X
}
C {sky130_fd_pr/nfet_01v8.sym} 2100 -120 2 1 {name=M51
L=0.15
W=1
nf=1 
mult=1
ad="'int((nf+1)/2) * W/nf * 0.29'" 
pd="'2*int((nf+1)/2) * (W/nf + 0.29)'"
as="'int((nf+2)/2) * W/nf * 0.29'" 
ps="'2*int((nf+2)/2) * (W/nf + 0.29)'"
nrd="'0.29 / W'" nrs="'0.29 / W'"
sa=0 sb=0 sd=0
model=nfet_01v8
spiceprefix=X
}
C {devices/vdd.sym} 2120 -250 0 1 {lab=VDD}
C {devices/gnd.sym} 2120 -80 0 1 {name=l39 lab=GND}
C {sky130_fd_pr/pfet_01v8.sym} 2280 -210 2 1 {name=M52
L=0.15
W=1
nf=1
mult=1
ad="'int((nf+1)/2) * W/nf * 0.29'" 
pd="'2*int((nf+1)/2) * (W/nf + 0.29)'"
as="'int((nf+2)/2) * W/nf * 0.29'" 
ps="'2*int((nf+2)/2) * (W/nf + 0.29)'"
nrd="'0.29 / W'" nrs="'0.29 / W'"
sa=0 sb=0 sd=0
model=pfet_01v8
spiceprefix=X
}
C {sky130_fd_pr/nfet_01v8.sym} 2280 -120 2 1 {name=M53
L=0.15
W=1
nf=1 
mult=1
ad="'int((nf+1)/2) * W/nf * 0.29'" 
pd="'2*int((nf+1)/2) * (W/nf + 0.29)'"
as="'int((nf+2)/2) * W/nf * 0.29'" 
ps="'2*int((nf+2)/2) * (W/nf + 0.29)'"
nrd="'0.29 / W'" nrs="'0.29 / W'"
sa=0 sb=0 sd=0
model=nfet_01v8
spiceprefix=X
}
C {devices/vdd.sym} 2300 -250 0 1 {lab=VDD}
C {devices/gnd.sym} 2300 -80 0 1 {name=l40 lab=GND}
C {sky130_fd_pr/pfet_01v8.sym} 2460 -210 2 1 {name=M54
L=0.15
W=1
nf=1
mult=1
ad="'int((nf+1)/2) * W/nf * 0.29'" 
pd="'2*int((nf+1)/2) * (W/nf + 0.29)'"
as="'int((nf+2)/2) * W/nf * 0.29'" 
ps="'2*int((nf+2)/2) * (W/nf + 0.29)'"
nrd="'0.29 / W'" nrs="'0.29 / W'"
sa=0 sb=0 sd=0
model=pfet_01v8
spiceprefix=X
}
C {sky130_fd_pr/nfet_01v8.sym} 2460 -120 2 1 {name=M55
L=0.15
W=1
nf=1 
mult=1
ad="'int((nf+1)/2) * W/nf * 0.29'" 
pd="'2*int((nf+1)/2) * (W/nf + 0.29)'"
as="'int((nf+2)/2) * W/nf * 0.29'" 
ps="'2*int((nf+2)/2) * (W/nf + 0.29)'"
nrd="'0.29 / W'" nrs="'0.29 / W'"
sa=0 sb=0 sd=0
model=nfet_01v8
spiceprefix=X
}
C {devices/vdd.sym} 2480 -250 0 1 {lab=VDD}
C {devices/gnd.sym} 2480 -80 0 1 {name=l41 lab=GND}
